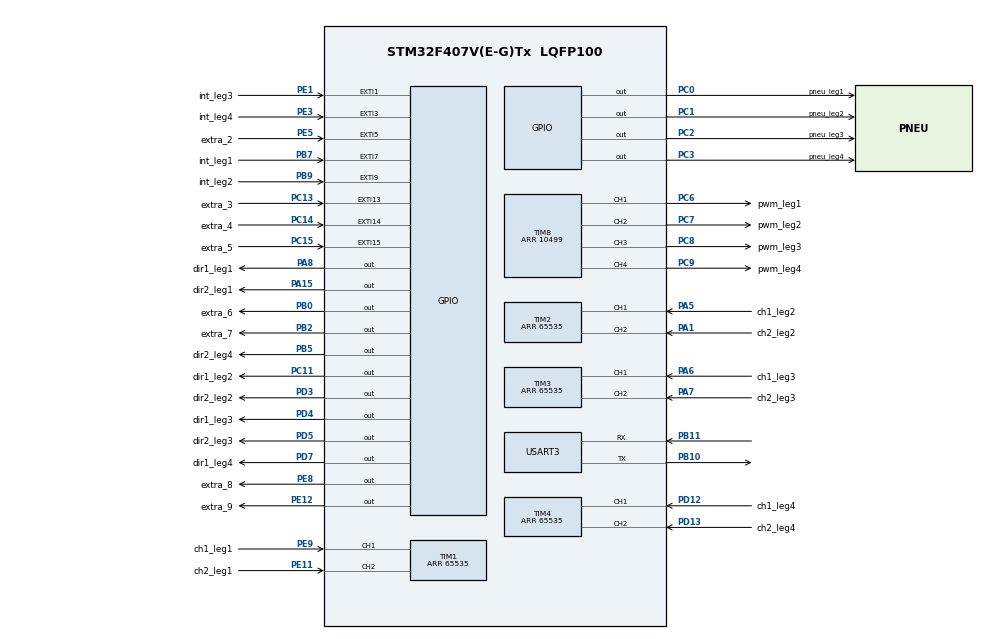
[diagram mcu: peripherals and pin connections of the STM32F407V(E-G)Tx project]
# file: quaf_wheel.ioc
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Dma.Request0=USART3_RX
Dma.Request1=USART3_TX
Dma.USART3_RX.0.Direction=DMA_PERIPH_TO_MEMORY
Dma.USART3_RX.0.FIFOMode=DMA_FIFOMODE_DISABLE
Dma.USART3_RX.0.Instance=DMA1_Stream1
Dma.USART3_RX.0.MemDataAlignment=DMA_MDATAALIGN_BYTE
Dma.USART3_RX.0.MemInc=DMA_MINC_ENABLE
Dma.USART3_RX.0.Mode=DMA_NORMAL
Dma.USART3_RX.0.PeriphDataAlignment=DMA_PDATAALIGN_BYTE
Dma.USART3_RX.0.PeriphInc=DMA_PINC_DISABLE
Dma.USART3_RX.0.Priority=DMA_PRIORITY_LOW
Dma.USART3_TX.1.Direction=DMA_MEMORY_TO_PERIPH
Dma.USART3_TX.1.FIFOMode=DMA_FIFOMODE_DISABLE
Dma.USART3_TX.1.Instance=DMA1_Stream3
Dma.USART3_TX.1.MemDataAlignment=DMA_MDATAALIGN_BYTE
Dma.USART3_TX.1.MemInc=DMA_MINC_ENABLE
Dma.USART3_TX.1.Mode=DMA_NORMAL
Dma.USART3_TX.1.PeriphDataAlignment=DMA_PDATAALIGN_BYTE
Dma.USART3_TX.1.PeriphInc=DMA_PINC_DISABLE
Dma.USART3_TX.1.Priority=DMA_PRIORITY_LOW
Mcu.Family=STM32F4
Mcu.Name=STM32F407V(E-G)Tx
Mcu.Package=LQFP100
NVIC.DMA1_Stream1_IRQn=true\:0\:0\:false\:false\:true\:false
NVIC.DMA1_Stream3_IRQn=true\:0\:0\:false\:false\:true\:false
NVIC.EXTI15_10_IRQn=true\:0\:0\:false\:false\:true\:true
NVIC.EXTI1_IRQn=true\:0\:0\:false\:false\:true\:true
NVIC.EXTI3_IRQn=true\:0\:0\:false\:false\:true\:true
NVIC.EXTI9_5_IRQn=true\:0\:0\:false\:false\:true\:true
NVIC.PriorityGroup=NVIC_PRIORITYGROUP_4
NVIC.USART3_IRQn=true\:0\:0\:false\:false\:true\:true
PA1.GPIO_Label=ch2_leg2
PA1.GPIO_PuPd=GPIO_PULLUP
PA1.GPIO_Speed=GPIO_SPEED_FREQ_VERY_HIGH
PA1.Signal=S_TIM2_CH2
PA13.Mode=Trace_Asynchronous_SW
PA13.Signal=SYS_JTMS-SWDIO
PA14.Mode=Trace_Asynchronous_SW
PA14.Signal=SYS_JTCK-SWCLK
PA15.GPIO_Label=dir2_leg1
PA15.Signal=GPIO_Output
PA5.GPIO_Label=ch1_leg2
PA5.GPIO_PuPd=GPIO_PULLUP
PA5.GPIO_Speed=GPIO_SPEED_FREQ_VERY_HIGH
PA5.Signal=S_TIM2_CH1_ETR
PA6.GPIO_Label=ch1_leg3
PA6.GPIO_PuPd=GPIO_PULLUP
PA6.GPIO_Speed=GPIO_SPEED_FREQ_VERY_HIGH
PA6.Signal=S_TIM3_CH1
PA7.GPIO_Label=ch2_leg3
PA7.GPIO_PuPd=GPIO_PULLUP
PA7.GPIO_Speed=GPIO_SPEED_FREQ_VERY_HIGH
PA7.Signal=S_TIM3_CH2
PA8.GPIO_Label=dir1_leg1
PA8.Signal=GPIO_Output
PB0.GPIO_Label=extra_6
PB0.Signal=GPIO_Output
PB10.Mode=Asynchronous
PB10.Signal=USART3_TX
PB11.Mode=Asynchronous
PB11.Signal=USART3_RX
PB2.GPIO_Label=extra_7
PB2.Signal=GPIO_Output
PB3.Mode=Trace_Asynchronous_SW
PB3.Signal=SYS_JTDO-SWO
PB5.GPIO_Label=dir2_leg4
PB5.Signal=GPIO_Output
PB7.GPIO_Label=int_leg1
PB7.GPIO_ModeDefaultEXTI=GPIO_MODE_IT_FALLING
PB7.GPIO_PuPd=GPIO_PULLUP
PB7.Signal=GPXTI7
PB9.GPIO_Label=int_leg2
PB9.GPIO_ModeDefaultEXTI=GPIO_MODE_IT_FALLING
PB9.GPIO_PuPd=GPIO_PULLUP
PB9.Signal=GPXTI9
PC0.GPIO_Label=pneu_leg1
PC0.Signal=GPIO_Output
PC1.GPIO_Label=pneu_leg2
PC1.Signal=GPIO_Output
PC11.GPIO_Label=dir1_leg2
PC11.Signal=GPIO_Output
PC13-ANTI_TAMP.GPIO_Label=extra_3
PC13-ANTI_TAMP.GPIO_ModeDefaultEXTI=GPIO_MODE_IT_FALLING
PC13-ANTI_TAMP.GPIO_PuPd=GPIO_PULLUP
PC13-ANTI_TAMP.Signal=GPXTI13
PC14-OSC32_IN.GPIO_Label=extra_4
PC14-OSC32_IN.GPIO_PuPd=GPIO_PULLUP
PC14-OSC32_IN.Signal=GPXTI14
PC15-OSC32_OUT.GPIO_Label=extra_5
PC15-OSC32_OUT.GPIO_PuPd=GPIO_PULLUP
PC15-OSC32_OUT.Signal=GPXTI15
PC2.GPIO_Label=pneu_leg3
PC2.Signal=GPIO_Output
PC3.GPIO_Label=pneu_leg4
PC3.Signal=GPIO_Output
PC6.GPIO_Label=pwm_leg1
PC6.GPIO_Speed=GPIO_SPEED_FREQ_VERY_HIGH
PC6.Signal=S_TIM8_CH1
PC7.GPIO_Label=pwm_leg2
PC7.GPIO_Speed=GPIO_SPEED_FREQ_VERY_HIGH
PC7.Signal=S_TIM8_CH2
PC8.GPIO_Label=pwm_leg3
PC8.GPIO_Speed=GPIO_SPEED_FREQ_VERY_HIGH
PC8.Signal=S_TIM8_CH3
PC9.GPIO_Label=pwm_leg4
PC9.GPIO_Speed=GPIO_SPEED_FREQ_VERY_HIGH
PC9.Signal=S_TIM8_CH4
PD12.GPIO_Label=ch1_leg4
PD12.GPIO_PuPd=GPIO_PULLUP
PD12.GPIO_Speed=GPIO_SPEED_FREQ_VERY_HIGH
PD12.Signal=S_TIM4_CH1
PD13.GPIO_Label=ch2_leg4
PD13.GPIO_PuPd=GPIO_PULLUP
PD13.GPIO_Speed=GPIO_SPEED_FREQ_VERY_HIGH
PD13.Signal=S_TIM4_CH2
PD3.GPIO_Label=dir2_leg2
PD3.Signal=GPIO_Output
PD4.GPIO_Label=dir1_leg3
PD4.Signal=GPIO_Output
PD5.GPIO_Label=dir2_leg3
PD5.Signal=GPIO_Output
PD7.GPIO_Label=dir1_leg4
PD7.Signal=GPIO_Output
PE1.GPIO_Label=int_leg3
PE1.GPIO_ModeDefaultEXTI=GPIO_MODE_IT_FALLING
PE1.GPIO_PuPd=GPIO_PULLUP
PE1.Signal=GPXTI1
PE11.GPIO_Label=ch2_leg1
PE11.GPIO_PuPd=GPIO_PULLUP
PE11.GPIO_Speed=GPIO_SPEED_FREQ_VERY_HIGH
PE11.Signal=S_TIM1_CH2
PE12.GPIO_Label=extra_9
PE12.Signal=GPIO_Output
PE3.GPIO_Label=int_leg4
PE3.GPIO_ModeDefaultEXTI=GPIO_MODE_IT_FALLING
PE3.GPIO_PuPd=GPIO_PULLUP
PE3.Signal=GPXTI3
PE5.GPIO_Label=extra_2
PE5.GPIO_PuPd=GPIO_PULLUP
PE5.Signal=GPXTI5
PE8.GPIO_Label=extra_8
PE8.Signal=GPIO_Output
PE9.GPIO_Label=ch1_leg1
PE9.GPIO_PuPd=GPIO_PULLUP
PE9.GPIO_Speed=GPIO_SPEED_FREQ_VERY_HIGH
PE9.Signal=S_TIM1_CH1
PH0-OSC_IN.Mode=HSE-External-Oscillator
PH0-OSC_IN.Signal=RCC_OSC_IN
PH1-OSC_OUT.Mode=HSE-External-Oscillator
PH1-OSC_OUT.Signal=RCC_OSC_OUT
ProjectManager.HeapSize=0x200
ProjectManager.StackSize=0x400
ProjectManager.TargetToolchain=MDK-ARM V5
RCC.48MHZClocksFreq_Value=84000000
RCC.AHBFreq_Value=168000000
RCC.APB1CLKDivider=RCC_HCLK_DIV4
RCC.APB1Freq_Value=42000000
RCC.APB1TimFreq_Value=84000000
RCC.APB2CLKDivider=RCC_HCLK_DIV2
RCC.APB2Freq_Value=84000000
RCC.APB2TimFreq_Value=168000000
RCC.CortexFreq_Value=168000000
RCC.HCLKFreq_Value=168000000
RCC.HSE_VALUE=25000000
RCC.HSI_VALUE=16000000
RCC.LSE_VALUE=32768
RCC.PLLM=8
RCC.PLLN=168
RCC.SYSCLKFreq_VALUE=168000000
RCC.SYSCLKSource=RCC_SYSCLKSOURCE_PLLCLK
RCC.VCOOutputFreq_Value=336000000
SH.S_TIM1_CH1.0=TIM1_CH1,Encoder_Interface
SH.S_TIM1_CH2.0=TIM1_CH2,Encoder_Interface
SH.S_TIM2_CH1_ETR.0=TIM2_CH1,Encoder_Interface
SH.S_TIM2_CH2.0=TIM2_CH2,Encoder_Interface
SH.S_TIM3_CH1.0=TIM3_CH1,Encoder_Interface
SH.S_TIM3_CH2.0=TIM3_CH2,Encoder_Interface
SH.S_TIM4_CH1.0=TIM4_CH1,Encoder_Interface
SH.S_TIM4_CH2.0=TIM4_CH2,Encoder_Interface
SH.S_TIM8_CH1.0=TIM8_CH1,PWM Generation1 CH1
SH.S_TIM8_CH2.0=TIM8_CH2,PWM Generation2 CH2
SH.S_TIM8_CH3.0=TIM8_CH3,PWM Generation3 CH3
SH.S_TIM8_CH4.0=TIM8_CH4,PWM Generation4 CH4
TIM1.EncoderMode=TIM_ENCODERMODE_TI12
TIM1.Period=65535
TIM2.EncoderMode=TIM_ENCODERMODE_TI12
TIM2.Period=65535
TIM3.EncoderMode=TIM_ENCODERMODE_TI12
TIM3.Period=65535
TIM4.EncoderMode=TIM_ENCODERMODE_TI12
TIM4.Period=65535
TIM8.Channel-PWM\ Generation1\ CH1=TIM_CHANNEL_1
TIM8.Channel-PWM\ Generation2\ CH2=TIM_CHANNEL_2
TIM8.Channel-PWM\ Generation3\ CH3=TIM_CHANNEL_3
TIM8.Channel-PWM\ Generation4\ CH4=TIM_CHANNEL_4
TIM8.CounterMode=TIM_COUNTERMODE_CENTERALIGNED1
TIM8.Period=10499
USART3.VirtualMode=VM_ASYNC
board=custom

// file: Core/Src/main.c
/**
  ******************************************************************************
  * @file           : main.c
  * @brief          : Main program body
  ******************************************************************************
  ** This notice applies to any and all portions of this file
  * that are not between comment pairs USER CODE BEGIN and
  * USER CODE END. Other portions of this file, whether
  * inserted by the user or by software development tools
  * are owned by their respective copyright owners.
  *
  * COPYRIGHT(c) 2018 STMicroelectronics
  *
  * Redistribution and use in source and binary forms, with or without modification,
  * are permitted provided that the following conditions are met:
  *   1. Redistributions of source code must retain the above copyright notice,
  *      this list of conditions and the following disclaimer.
  *   2. Redistributions in binary form must reproduce the above copyright notice,
  *      this list of conditions and the following disclaimer in the documentation
  *      and/or other materials provided with the distribution.
  *   3. Neither the name of STMicroelectronics nor the names of its contributors
  *      may be used to endorse or promote products derived from this software
  *      without specific prior written permission.
  *
  * THIS SOFTWARE IS PROVIDED BY THE COPYRIGHT HOLDERS AND CONTRIBUTORS "AS IS"
  * AND ANY EXPRESS OR IMPLIED WARRANTIES, INCLUDING, BUT NOT LIMITED TO, THE
  * IMPLIED WARRANTIES OF MERCHANTABILITY AND FITNESS FOR A PARTICULAR PURPOSE ARE
  * DISCLAIMED. IN NO EVENT SHALL THE COPYRIGHT HOLDER OR CONTRIBUTORS BE LIABLE
  * FOR ANY DIRECT, INDIRECT, INCIDENTAL, SPECIAL, EXEMPLARY, OR CONSEQUENTIAL
  * DAMAGES (INCLUDING, BUT NOT LIMITED TO, PROCUREMENT OF SUBSTITUTE GOODS OR
  * SERVICES; LOSS OF USE, DATA, OR PROFITS; OR BUSINESS INTERRUPTION) HOWEVER
  * CAUSED AND ON ANY THEORY OF LIABILITY, WHETHER IN CONTRACT, STRICT LIABILITY,
  * OR TORT (INCLUDING NEGLIGENCE OR OTHERWISE) ARISING IN ANY WAY OUT OF THE USE
  * OF THIS SOFTWARE, EVEN IF ADVISED OF THE POSSIBILITY OF SUCH DAMAGE.
  *
  ******************************************************************************
  */
#include "main.h"
#include "stm32f4xx_hal.h"
#include "tim.h"
#include "usart.h"
#include "gpio.h"

/* USER CODE BEGIN Includes */
#include "robo_init.h"
#include "pid.h"
#include <stdlib.h>
#include "motionProfile.h"
#include "leg.h"
#include "gait.h"

#define CALIBRATE_SPEED (-4.0) /* In omega */
#define HOME_POS_OMEGA (-4.0)
#define MAX_POSSIBLE_ANGLE (140)

/* USER CODE END Includes */

/* USER CODE BEGIN PV */

    // global variables
    int16_t ref_cnt[4]   = {0, 0, 0, 0};          // last count when interrupt occured
    int16_t curr_cnt[4]  = {0, 0, 0, 0};          // current count for angle calculation
    uint16_t last_cnt[4] = {0, 0, 0, 0};

    float inst_angle[4]     = {0, 0, 0, 0};       // angle at the instant
    float update_omega[4]   = {0, 0, 0, 0};

    uint32_t dt_ms = 9L;
    float dt_secs  = 0.009;

    float all_set_points;

    //global flags
    uint8_t _PHASE = 0;
    uint16_t _CHECK_VARIABLE = 111;
    uint8_t _PHASE_CHANGE_FLAG = 0;
    uint8_t _RAISE_MOTOR_INDEX = 0;
    uint8_t _START_LOOP_FLAG = 0;
    uint8_t _NEXT_MOTOR_FLAG = 0;

/* Private variables ---------------------------------------------------------*/

/* USER CODE END PV */

void SystemClock_Config(void);

/* USER CODE BEGIN PFP */
/* Private function prototypes -----------------------------------------------*/

/* USER CODE END PFP */

/* USER CODE BEGIN 0 */

struct __FILE{

int handle;
};

FILE __stdout;
FILE __stdin;

int fputc(int ch, FILE *f)
{
	ITM_SendChar(ch);
	return(ch);
}

/*void calculate_setPoints()
{

    for(int i=0; i<4; i++)
    {
        int16_t counts_per_st = curr_cnt[i] - last_cnt[i];
        last_cnt[i]      = curr_cnt[i];

        float omega      = 0.71922 * counts_per_st / dt_ms;
        if((i == _RAISE_MOTOR_INDEX) && !_START_LOOP_FLAG)
        {
            raise_Leg(&leg_arr[_RAISE_MOTOR_INDEX]);

		    int temp_angle = i * (-60);
            motionProfile_setAngle(&profile_arr[i], temp_angle);

            float set_point  = motionProfile_Generate(&profile_arr[i],inst_angle[i]);
            update_omega[i]  = pid_Compute(&pid[i], set_point, omega, dt_ms);

            if((profile_arr[i].status == COMPLETE) && (inst_angle[i] >= temp_angle))
            {
                _START_LOOP_FLAG = 1;
                update_omega[_RAISE_MOTOR_INDEX] = 0;

            }

        }

       if((i != _RAISE_MOTOR_INDEX) && _START_LOOP_FLAG )
       {
           motionProfile_setAngle(&profile_arr[i],60);
           float set_point  = motionProfile_Generate(&profile_arr[i],inst_angle[i]);
           update_omega[i]  = pid_Compute(&pid[i], set_point, omega, dt_ms);
       }
    }
} */

/* USER CODE END 0 */

int main(void)
{
  	/* USER CODE BEGIN 1 */

	uint32_t update_tick = HAL_GetTick();

  	/* USER CODE END 1 */

  	/* MCU Configuration----------------------------------------------------------*/

  	/* Reset of all peripherals, Initializes the Flash interface and the Systick. */

  	HAL_Init();

  	/* Configure the system clock */
  	SystemClock_Config();

  	/* Initialize all configured peripherals */
  	MX_GPIO_Init();
  	MX_TIM8_Init();
  	MX_USART3_UART_Init();
  	MX_TIM1_Init();
  	MX_TIM2_Init();
  	MX_TIM3_Init();
  	MX_TIM4_Init();
  	/* USER CODE BEGIN 2 */

	robot_init();
  	/* USER CODE END 2 */

  	/* Infinite loop */
  	/* USER
  	CODE BEGIN WHILE */

  	set_HomePosition();

  	while(1)
	{
  	     	if((HAL_GetTick()- update_tick) > dt_ms)
  	      	{
  	      		update_tick   = HAL_GetTick();
			start_Gallop();
  	      	}

  	}
  /* USER CODE END WHILE */

}

void SystemClock_Config(void)
{

  RCC_OscInitTypeDef RCC_OscInitStruct;
  RCC_ClkInitTypeDef RCC_ClkInitStruct;

    /**Configure the main internal regulator output voltage
    */
  __HAL_RCC_PWR_CLK_ENABLE();

  __HAL_PWR_VOLTAGESCALING_CONFIG(PWR_REGULATOR_VOLTAGE_SCALE1);

    /**Initializes the CPU, AHB and APB busses clocks
    */
  RCC_OscInitStruct.OscillatorType = RCC_OSCILLATORTYPE_HSE;
  RCC_OscInitStruct.HSEState = RCC_HSE_ON;
  RCC_OscInitStruct.PLL.PLLState = RCC_PLL_ON;
  RCC_OscInitStruct.PLL.PLLSource = RCC_PLLSOURCE_HSE;
  RCC_OscInitStruct.PLL.PLLM = 8;
  RCC_OscInitStruct.PLL.PLLN = 336;
  RCC_OscInitStruct.PLL.PLLP = RCC_PLLP_DIV2;
  RCC_OscInitStruct.PLL.PLLQ = 4;
  if (HAL_RCC_OscConfig(&RCC_OscInitStruct) != HAL_OK)
  {
    _Error_Handler(__FILE__, __LINE__);
  }

    /**Initializes the CPU, AHB and APB busses clocks
    */
  RCC_ClkInitStruct.ClockType = RCC_CLOCKTYPE_HCLK|RCC_CLOCKTYPE_SYSCLK
                              |RCC_CLOCKTYPE_PCLK1|RCC_CLOCKTYPE_PCLK2;
  RCC_ClkInitStruct.SYSCLKSource = RCC_SYSCLKSOURCE_PLLCLK;
  RCC_ClkInitStruct.AHBCLKDivider = RCC_SYSCLK_DIV1;
  RCC_ClkInitStruct.APB1CLKDivider = RCC_HCLK_DIV4;
  RCC_ClkInitStruct.APB2CLKDivider = RCC_HCLK_DIV2;

  if (HAL_RCC_ClockConfig(&RCC_ClkInitStruct, FLASH_LATENCY_5) != HAL_OK)
  {
    _Error_Handler(__FILE__, __LINE__);
  }

    /**Configure the Systick interrupt time
    */
  HAL_SYSTICK_Config(HAL_RCC_GetHCLKFreq()/1000);

    /**Configure the Systick
    */
  HAL_SYSTICK_CLKSourceConfig(SYSTICK_CLKSOURCE_HCLK);

  /* SysTick_IRQn interrupt configuration */
  HAL_NVIC_SetPriority(SysTick_IRQn, 0, 0);
}

void _Error_Handler(char *file, int line)
{
        while (1)
        {
        }
}

/************************ (C) COPYRIGHT STMicroelectronics *****END OF FILE****/
